# Generated by FakeRAM 2.0 (routing-friendly)
VERSION 5.7 ;
BUSBITCHARS "[]" ;
PROPERTYDEFINITIONS
  MACRO width INTEGER ;
  MACRO depth INTEGER ;
  MACRO banks INTEGER ;
END PROPERTYDEFINITIONS
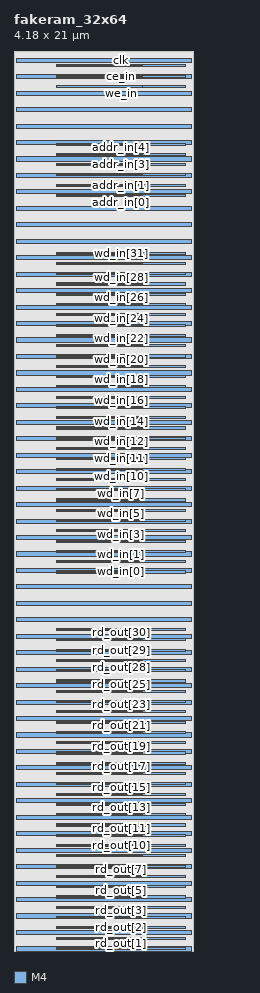
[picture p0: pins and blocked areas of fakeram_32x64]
MACRO fakeram_32x64
  PROPERTY width 32 ;
  PROPERTY depth 64 ;
  PROPERTY banks 1 ;
  FOREIGN fakeram_32x64 0 0 ;
  SYMMETRY X Y R90 ;
  SIZE 4.180 BY 21.000 ;
  CLASS BLOCK ;
  PIN rd_out[0]
    DIRECTION OUTPUT ;
    USE SIGNAL ;
    PORT
      LAYER M4 ;
      RECT 1.000 0.048 3.000 0.072 ;
    END
    PORT
      LAYER M4 ;
      RECT 1.000 0.036 4.000 0.084 ;
    END
  END rd_out[0]
  PIN rd_out[1]
    DIRECTION OUTPUT ;
    USE SIGNAL ;
    PORT
      LAYER M4 ;
      RECT 1.000 0.288 3.000 0.312 ;
    END
    PORT
      LAYER M4 ;
      RECT 1.000 0.276 4.000 0.324 ;
    END
  END rd_out[1]
  PIN rd_out[2]
    DIRECTION OUTPUT ;
    USE SIGNAL ;
    PORT
      LAYER M4 ;
      RECT 1.000 0.528 3.000 0.552 ;
    END
    PORT
      LAYER M4 ;
      RECT 1.000 0.516 4.000 0.564 ;
    END
  END rd_out[2]
  PIN rd_out[3]
    DIRECTION OUTPUT ;
    USE SIGNAL ;
    PORT
      LAYER M4 ;
      RECT 1.000 0.768 3.000 0.792 ;
    END
    PORT
      LAYER M4 ;
      RECT 1.000 0.756 4.000 0.804 ;
    END
  END rd_out[3]
  PIN rd_out[4]
    DIRECTION OUTPUT ;
    USE SIGNAL ;
    PORT
      LAYER M4 ;
      RECT 1.000 1.008 3.000 1.032 ;
    END
    PORT
      LAYER M4 ;
      RECT 1.000 0.996 4.000 1.044 ;
    END
  END rd_out[4]
  PIN rd_out[5]
    DIRECTION OUTPUT ;
    USE SIGNAL ;
    PORT
      LAYER M4 ;
      RECT 1.000 1.248 3.000 1.272 ;
    END
    PORT
      LAYER M4 ;
      RECT 1.000 1.236 4.000 1.284 ;
    END
  END rd_out[5]
  PIN rd_out[6]
    DIRECTION OUTPUT ;
    USE SIGNAL ;
    PORT
      LAYER M4 ;
      RECT 1.000 1.488 3.000 1.512 ;
    END
    PORT
      LAYER M4 ;
      RECT 1.000 1.476 4.000 1.524 ;
    END
  END rd_out[6]
  PIN rd_out[7]
    DIRECTION OUTPUT ;
    USE SIGNAL ;
    PORT
      LAYER M4 ;
      RECT 1.000 1.728 3.000 1.752 ;
    END
    PORT
      LAYER M4 ;
      RECT 1.000 1.716 4.000 1.764 ;
    END
  END rd_out[7]
  PIN rd_out[8]
    DIRECTION OUTPUT ;
    USE SIGNAL ;
    PORT
      LAYER M4 ;
      RECT 1.000 1.968 3.000 1.992 ;
    END
    PORT
      LAYER M4 ;
      RECT 1.000 1.956 4.000 2.004 ;
    END
  END rd_out[8]
  PIN rd_out[9]
    DIRECTION OUTPUT ;
    USE SIGNAL ;
    PORT
      LAYER M4 ;
      RECT 1.000 2.208 3.000 2.232 ;
    END
    PORT
      LAYER M4 ;
      RECT 1.000 2.196 4.000 2.244 ;
    END
  END rd_out[9]
  PIN rd_out[10]
    DIRECTION OUTPUT ;
    USE SIGNAL ;
    PORT
      LAYER M4 ;
      RECT 1.000 2.448 3.000 2.472 ;
    END
    PORT
      LAYER M4 ;
      RECT 1.000 2.436 4.000 2.484 ;
    END
  END rd_out[10]
  PIN rd_out[11]
    DIRECTION OUTPUT ;
    USE SIGNAL ;
    PORT
      LAYER M4 ;
      RECT 1.000 2.688 3.000 2.712 ;
    END
    PORT
      LAYER M4 ;
      RECT 1.000 2.676 4.000 2.724 ;
    END
  END rd_out[11]
  PIN rd_out[12]
    DIRECTION OUTPUT ;
    USE SIGNAL ;
    PORT
      LAYER M4 ;
      RECT 1.000 2.928 3.000 2.952 ;
    END
    PORT
      LAYER M4 ;
      RECT 1.000 2.916 4.000 2.964 ;
    END
  END rd_out[12]
  PIN rd_out[13]
    DIRECTION OUTPUT ;
    USE SIGNAL ;
    PORT
      LAYER M4 ;
      RECT 1.000 3.168 3.000 3.192 ;
    END
    PORT
      LAYER M4 ;
      RECT 1.000 3.156 4.000 3.204 ;
    END
  END rd_out[13]
  PIN rd_out[14]
    DIRECTION OUTPUT ;
    USE SIGNAL ;
    PORT
      LAYER M4 ;
      RECT 1.000 3.408 3.000 3.432 ;
    END
    PORT
      LAYER M4 ;
      RECT 1.000 3.396 4.000 3.444 ;
    END
  END rd_out[14]
  PIN rd_out[15]
    DIRECTION OUTPUT ;
    USE SIGNAL ;
    PORT
      LAYER M4 ;
      RECT 1.000 3.648 3.000 3.672 ;
    END
    PORT
      LAYER M4 ;
      RECT 1.000 3.636 4.000 3.684 ;
    END
  END rd_out[15]
  PIN rd_out[16]
    DIRECTION OUTPUT ;
    USE SIGNAL ;
    PORT
      LAYER M4 ;
      RECT 1.000 3.888 3.000 3.912 ;
    END
    PORT
      LAYER M4 ;
      RECT 1.000 3.876 4.000 3.924 ;
    END
  END rd_out[16]
  PIN rd_out[17]
    DIRECTION OUTPUT ;
    USE SIGNAL ;
    PORT
      LAYER M4 ;
      RECT 1.000 4.128 3.000 4.152 ;
    END
    PORT
      LAYER M4 ;
      RECT 1.000 4.116 4.000 4.164 ;
    END
  END rd_out[17]
  PIN rd_out[18]
    DIRECTION OUTPUT ;
    USE SIGNAL ;
    PORT
      LAYER M4 ;
      RECT 1.000 4.368 3.000 4.392 ;
    END
    PORT
      LAYER M4 ;
      RECT 1.000 4.356 4.000 4.404 ;
    END
  END rd_out[18]
  PIN rd_out[19]
    DIRECTION OUTPUT ;
    USE SIGNAL ;
    PORT
      LAYER M4 ;
      RECT 1.000 4.608 3.000 4.632 ;
    END
    PORT
      LAYER M4 ;
      RECT 1.000 4.596 4.000 4.644 ;
    END
  END rd_out[19]
  PIN rd_out[20]
    DIRECTION OUTPUT ;
    USE SIGNAL ;
    PORT
      LAYER M4 ;
      RECT 1.000 4.848 3.000 4.872 ;
    END
    PORT
      LAYER M4 ;
      RECT 1.000 4.836 4.000 4.884 ;
    END
  END rd_out[20]
  PIN rd_out[21]
    DIRECTION OUTPUT ;
    USE SIGNAL ;
    PORT
      LAYER M4 ;
      RECT 1.000 5.088 3.000 5.112 ;
    END
    PORT
      LAYER M4 ;
      RECT 1.000 5.076 4.000 5.124 ;
    END
  END rd_out[21]
  PIN rd_out[22]
    DIRECTION OUTPUT ;
    USE SIGNAL ;
    PORT
      LAYER M4 ;
      RECT 1.000 5.328 3.000 5.352 ;
    END
    PORT
      LAYER M4 ;
      RECT 1.000 5.316 4.000 5.364 ;
    END
  END rd_out[22]
  PIN rd_out[23]
    DIRECTION OUTPUT ;
    USE SIGNAL ;
    PORT
      LAYER M4 ;
      RECT 1.000 5.568 3.000 5.592 ;
    END
    PORT
      LAYER M4 ;
      RECT 1.000 5.556 4.000 5.604 ;
    END
  END rd_out[23]
  PIN rd_out[24]
    DIRECTION OUTPUT ;
    USE SIGNAL ;
    PORT
      LAYER M4 ;
      RECT 1.000 5.808 3.000 5.832 ;
    END
    PORT
      LAYER M4 ;
      RECT 1.000 5.796 4.000 5.844 ;
    END
  END rd_out[24]
  PIN rd_out[25]
    DIRECTION OUTPUT ;
    USE SIGNAL ;
    PORT
      LAYER M4 ;
      RECT 1.000 6.048 3.000 6.072 ;
    END
    PORT
      LAYER M4 ;
      RECT 1.000 6.036 4.000 6.084 ;
    END
  END rd_out[25]
  PIN rd_out[26]
    DIRECTION OUTPUT ;
    USE SIGNAL ;
    PORT
      LAYER M4 ;
      RECT 1.000 6.288 3.000 6.312 ;
    END
    PORT
      LAYER M4 ;
      RECT 1.000 6.276 4.000 6.324 ;
    END
  END rd_out[26]
  PIN rd_out[27]
    DIRECTION OUTPUT ;
    USE SIGNAL ;
    PORT
      LAYER M4 ;
      RECT 1.000 6.528 3.000 6.552 ;
    END
    PORT
      LAYER M4 ;
      RECT 1.000 6.516 4.000 6.564 ;
    END
  END rd_out[27]
  PIN rd_out[28]
    DIRECTION OUTPUT ;
    USE SIGNAL ;
    PORT
      LAYER M4 ;
      RECT 1.000 6.768 3.000 6.792 ;
    END
    PORT
      LAYER M4 ;
      RECT 1.000 6.756 4.000 6.804 ;
    END
  END rd_out[28]
  PIN rd_out[29]
    DIRECTION OUTPUT ;
    USE SIGNAL ;
    PORT
      LAYER M4 ;
      RECT 1.000 7.008 3.000 7.032 ;
    END
    PORT
      LAYER M4 ;
      RECT 1.000 6.996 4.000 7.044 ;
    END
  END rd_out[29]
  PIN rd_out[30]
    DIRECTION OUTPUT ;
    USE SIGNAL ;
    PORT
      LAYER M4 ;
      RECT 1.000 7.248 3.000 7.272 ;
    END
    PORT
      LAYER M4 ;
      RECT 1.000 7.236 4.000 7.284 ;
    END
  END rd_out[30]
  PIN rd_out[31]
    DIRECTION OUTPUT ;
    USE SIGNAL ;
    PORT
      LAYER M4 ;
      RECT 1.000 7.488 3.000 7.512 ;
    END
    PORT
      LAYER M4 ;
      RECT 1.000 7.476 4.000 7.524 ;
    END
  END rd_out[31]
  PIN wd_in[0]
    DIRECTION INPUT ;
    USE SIGNAL ;
    PORT
      LAYER M4 ;
      RECT 1.000 8.832 3.000 8.856 ;
    END
    PORT
      LAYER M4 ;
      RECT 1.000 8.820 4.000 8.868 ;
    END
  END wd_in[0]
  PIN wd_in[1]
    DIRECTION INPUT ;
    USE SIGNAL ;
    PORT
      LAYER M4 ;
      RECT 1.000 9.072 3.000 9.096 ;
    END
    PORT
      LAYER M4 ;
      RECT 1.000 9.060 4.000 9.108 ;
    END
  END wd_in[1]
  PIN wd_in[2]
    DIRECTION INPUT ;
    USE SIGNAL ;
    PORT
      LAYER M4 ;
      RECT 1.000 9.312 3.000 9.336 ;
    END
    PORT
      LAYER M4 ;
      RECT 1.000 9.300 4.000 9.348 ;
    END
  END wd_in[2]
  PIN wd_in[3]
    DIRECTION INPUT ;
    USE SIGNAL ;
    PORT
      LAYER M4 ;
      RECT 1.000 9.552 3.000 9.576 ;
    END
    PORT
      LAYER M4 ;
      RECT 1.000 9.540 4.000 9.588 ;
    END
  END wd_in[3]
  PIN wd_in[4]
    DIRECTION INPUT ;
    USE SIGNAL ;
    PORT
      LAYER M4 ;
      RECT 1.000 9.792 3.000 9.816 ;
    END
    PORT
      LAYER M4 ;
      RECT 1.000 9.780 4.000 9.828 ;
    END
  END wd_in[4]
  PIN wd_in[5]
    DIRECTION INPUT ;
    USE SIGNAL ;
    PORT
      LAYER M4 ;
      RECT 1.000 10.032 3.000 10.056 ;
    END
    PORT
      LAYER M4 ;
      RECT 1.000 10.020 4.000 10.068 ;
    END
  END wd_in[5]
  PIN wd_in[6]
    DIRECTION INPUT ;
    USE SIGNAL ;
    PORT
      LAYER M4 ;
      RECT 1.000 10.272 3.000 10.296 ;
    END
    PORT
      LAYER M4 ;
      RECT 1.000 10.260 4.000 10.308 ;
    END
  END wd_in[6]
  PIN wd_in[7]
    DIRECTION INPUT ;
    USE SIGNAL ;
    PORT
      LAYER M4 ;
      RECT 1.000 10.512 3.000 10.536 ;
    END
    PORT
      LAYER M4 ;
      RECT 1.000 10.500 4.000 10.548 ;
    END
  END wd_in[7]
  PIN wd_in[8]
    DIRECTION INPUT ;
    USE SIGNAL ;
    PORT
      LAYER M4 ;
      RECT 1.000 10.752 3.000 10.776 ;
    END
    PORT
      LAYER M4 ;
      RECT 1.000 10.740 4.000 10.788 ;
    END
  END wd_in[8]
  PIN wd_in[9]
    DIRECTION INPUT ;
    USE SIGNAL ;
    PORT
      LAYER M4 ;
      RECT 1.000 10.992 3.000 11.016 ;
    END
    PORT
      LAYER M4 ;
      RECT 1.000 10.980 4.000 11.028 ;
    END
  END wd_in[9]
  PIN wd_in[10]
    DIRECTION INPUT ;
    USE SIGNAL ;
    PORT
      LAYER M4 ;
      RECT 1.000 11.232 3.000 11.256 ;
    END
    PORT
      LAYER M4 ;
      RECT 1.000 11.220 4.000 11.268 ;
    END
  END wd_in[10]
  PIN wd_in[11]
    DIRECTION INPUT ;
    USE SIGNAL ;
    PORT
      LAYER M4 ;
      RECT 1.000 11.472 3.000 11.496 ;
    END
    PORT
      LAYER M4 ;
      RECT 1.000 11.460 4.000 11.508 ;
    END
  END wd_in[11]
  PIN wd_in[12]
    DIRECTION INPUT ;
    USE SIGNAL ;
    PORT
      LAYER M4 ;
      RECT 1.000 11.712 3.000 11.736 ;
    END
    PORT
      LAYER M4 ;
      RECT 1.000 11.700 4.000 11.748 ;
    END
  END wd_in[12]
  PIN wd_in[13]
    DIRECTION INPUT ;
    USE SIGNAL ;
    PORT
      LAYER M4 ;
      RECT 1.000 11.952 3.000 11.976 ;
    END
    PORT
      LAYER M4 ;
      RECT 1.000 11.940 4.000 11.988 ;
    END
  END wd_in[13]
  PIN wd_in[14]
    DIRECTION INPUT ;
    USE SIGNAL ;
    PORT
      LAYER M4 ;
      RECT 1.000 12.192 3.000 12.216 ;
    END
    PORT
      LAYER M4 ;
      RECT 1.000 12.180 4.000 12.228 ;
    END
  END wd_in[14]
  PIN wd_in[15]
    DIRECTION INPUT ;
    USE SIGNAL ;
    PORT
      LAYER M4 ;
      RECT 1.000 12.432 3.000 12.456 ;
    END
    PORT
      LAYER M4 ;
      RECT 1.000 12.420 4.000 12.468 ;
    END
  END wd_in[15]
  PIN wd_in[16]
    DIRECTION INPUT ;
    USE SIGNAL ;
    PORT
      LAYER M4 ;
      RECT 1.000 12.672 3.000 12.696 ;
    END
    PORT
      LAYER M4 ;
      RECT 1.000 12.660 4.000 12.708 ;
    END
  END wd_in[16]
  PIN wd_in[17]
    DIRECTION INPUT ;
    USE SIGNAL ;
    PORT
      LAYER M4 ;
      RECT 1.000 12.912 3.000 12.936 ;
    END
    PORT
      LAYER M4 ;
      RECT 1.000 12.900 4.000 12.948 ;
    END
  END wd_in[17]
  PIN wd_in[18]
    DIRECTION INPUT ;
    USE SIGNAL ;
    PORT
      LAYER M4 ;
      RECT 1.000 13.152 3.000 13.176 ;
    END
    PORT
      LAYER M4 ;
      RECT 1.000 13.140 4.000 13.188 ;
    END
  END wd_in[18]
  PIN wd_in[19]
    DIRECTION INPUT ;
    USE SIGNAL ;
    PORT
      LAYER M4 ;
      RECT 1.000 13.392 3.000 13.416 ;
    END
    PORT
      LAYER M4 ;
      RECT 1.000 13.380 4.000 13.428 ;
    END
  END wd_in[19]
  PIN wd_in[20]
    DIRECTION INPUT ;
    USE SIGNAL ;
    PORT
      LAYER M4 ;
      RECT 1.000 13.632 3.000 13.656 ;
    END
    PORT
      LAYER M4 ;
      RECT 1.000 13.620 4.000 13.668 ;
    END
  END wd_in[20]
  PIN wd_in[21]
    DIRECTION INPUT ;
    USE SIGNAL ;
    PORT
      LAYER M4 ;
      RECT 1.000 13.872 3.000 13.896 ;
    END
    PORT
      LAYER M4 ;
      RECT 1.000 13.860 4.000 13.908 ;
    END
  END wd_in[21]
  PIN wd_in[22]
    DIRECTION INPUT ;
    USE SIGNAL ;
    PORT
      LAYER M4 ;
      RECT 1.000 14.112 3.000 14.136 ;
    END
    PORT
      LAYER M4 ;
      RECT 1.000 14.100 4.000 14.148 ;
    END
  END wd_in[22]
  PIN wd_in[23]
    DIRECTION INPUT ;
    USE SIGNAL ;
    PORT
      LAYER M4 ;
      RECT 1.000 14.352 3.000 14.376 ;
    END
    PORT
      LAYER M4 ;
      RECT 1.000 14.340 4.000 14.388 ;
    END
  END wd_in[23]
  PIN wd_in[24]
    DIRECTION INPUT ;
    USE SIGNAL ;
    PORT
      LAYER M4 ;
      RECT 1.000 14.592 3.000 14.616 ;
    END
    PORT
      LAYER M4 ;
      RECT 1.000 14.580 4.000 14.628 ;
    END
  END wd_in[24]
  PIN wd_in[25]
    DIRECTION INPUT ;
    USE SIGNAL ;
    PORT
      LAYER M4 ;
      RECT 1.000 14.832 3.000 14.856 ;
    END
    PORT
      LAYER M4 ;
      RECT 1.000 14.820 4.000 14.868 ;
    END
  END wd_in[25]
  PIN wd_in[26]
    DIRECTION INPUT ;
    USE SIGNAL ;
    PORT
      LAYER M4 ;
      RECT 1.000 15.072 3.000 15.096 ;
    END
    PORT
      LAYER M4 ;
      RECT 1.000 15.060 4.000 15.108 ;
    END
  END wd_in[26]
  PIN wd_in[27]
    DIRECTION INPUT ;
    USE SIGNAL ;
    PORT
      LAYER M4 ;
      RECT 1.000 15.312 3.000 15.336 ;
    END
    PORT
      LAYER M4 ;
      RECT 1.000 15.300 4.000 15.348 ;
    END
  END wd_in[27]
  PIN wd_in[28]
    DIRECTION INPUT ;
    USE SIGNAL ;
    PORT
      LAYER M4 ;
      RECT 1.000 15.552 3.000 15.576 ;
    END
    PORT
      LAYER M4 ;
      RECT 1.000 15.540 4.000 15.588 ;
    END
  END wd_in[28]
  PIN wd_in[29]
    DIRECTION INPUT ;
    USE SIGNAL ;
    PORT
      LAYER M4 ;
      RECT 1.000 15.792 3.000 15.816 ;
    END
    PORT
      LAYER M4 ;
      RECT 1.000 15.780 4.000 15.828 ;
    END
  END wd_in[29]
  PIN wd_in[30]
    DIRECTION INPUT ;
    USE SIGNAL ;
    PORT
      LAYER M4 ;
      RECT 1.000 16.032 3.000 16.056 ;
    END
    PORT
      LAYER M4 ;
      RECT 1.000 16.020 4.000 16.068 ;
    END
  END wd_in[30]
  PIN wd_in[31]
    DIRECTION INPUT ;
    USE SIGNAL ;
    PORT
      LAYER M4 ;
      RECT 1.000 16.272 3.000 16.296 ;
    END
    PORT
      LAYER M4 ;
      RECT 1.000 16.260 4.000 16.308 ;
    END
  END wd_in[31]
  PIN addr_in[0]
    DIRECTION INPUT ;
    USE SIGNAL ;
    PORT
      LAYER M4 ;
      RECT 1.000 17.616 3.000 17.640 ;
    END
    PORT
      LAYER M4 ;
      RECT 1.000 17.604 4.000 17.652 ;
    END
  END addr_in[0]
  PIN addr_in[1]
    DIRECTION INPUT ;
    USE SIGNAL ;
    PORT
      LAYER M4 ;
      RECT 1.000 17.856 3.000 17.880 ;
    END
    PORT
      LAYER M4 ;
      RECT 1.000 17.844 4.000 17.892 ;
    END
  END addr_in[1]
  PIN addr_in[2]
    DIRECTION INPUT ;
    USE SIGNAL ;
    PORT
      LAYER M4 ;
      RECT 1.000 18.096 3.000 18.120 ;
    END
    PORT
      LAYER M4 ;
      RECT 1.000 18.084 4.000 18.132 ;
    END
  END addr_in[2]
  PIN addr_in[3]
    DIRECTION INPUT ;
    USE SIGNAL ;
    PORT
      LAYER M4 ;
      RECT 1.000 18.336 3.000 18.360 ;
    END
    PORT
      LAYER M4 ;
      RECT 1.000 18.324 4.000 18.372 ;
    END
  END addr_in[3]
  PIN addr_in[4]
    DIRECTION INPUT ;
    USE SIGNAL ;
    PORT
      LAYER M4 ;
      RECT 1.000 18.576 3.000 18.600 ;
    END
    PORT
      LAYER M4 ;
      RECT 1.000 18.564 4.000 18.612 ;
    END
  END addr_in[4]
  PIN addr_in[5]
    DIRECTION INPUT ;
    USE SIGNAL ;
    PORT
      LAYER M4 ;
      RECT 1.000 18.816 3.000 18.840 ;
    END
    PORT
      LAYER M4 ;
      RECT 1.000 18.804 4.000 18.852 ;
    END
  END addr_in[5]
  PIN we_in
    DIRECTION INPUT ;
    USE SIGNAL ;
    PORT
      LAYER M4 ;
      RECT 1.000 20.160 3.000 20.184 ;
    END
    PORT
      LAYER M4 ;
      RECT 1.000 20.148 4.000 20.196 ;
    END
  END we_in
  PIN ce_in
    DIRECTION INPUT ;
    USE SIGNAL ;
    PORT
      LAYER M4 ;
      RECT 1.000 20.400 3.000 20.424 ;
    END
    PORT
      LAYER M4 ;
      RECT 1.000 20.388 4.000 20.436 ;
    END
  END ce_in
  PIN clk
    DIRECTION INPUT ;
    USE SIGNAL ;
    PORT
      LAYER M4 ;
      RECT 1.000 20.640 3.000 20.664 ;
    END
    PORT
      LAYER M4 ;
      RECT 1.000 20.628 4.000 20.676 ;
    END
  END clk
  PIN VSS
    DIRECTION INOUT ;
    USE GROUND ;
    PORT
      LAYER M4 ;
      RECT 0.048 0.000 4.132 0.096 ;
      RECT 0.048 0.768 4.132 0.864 ;
      RECT 0.048 1.536 4.132 1.632 ;
      RECT 0.048 2.304 4.132 2.400 ;
      RECT 0.048 3.072 4.132 3.168 ;
      RECT 0.048 3.840 4.132 3.936 ;
      RECT 0.048 4.608 4.132 4.704 ;
      RECT 0.048 5.376 4.132 5.472 ;
      RECT 0.048 6.144 4.132 6.240 ;
      RECT 0.048 6.912 4.132 7.008 ;
      RECT 0.048 7.680 4.132 7.776 ;
      RECT 0.048 8.448 4.132 8.544 ;
      RECT 0.048 9.216 4.132 9.312 ;
      RECT 0.048 9.984 4.132 10.080 ;
      RECT 0.048 10.752 4.132 10.848 ;
      RECT 0.048 11.520 4.132 11.616 ;
      RECT 0.048 12.288 4.132 12.384 ;
      RECT 0.048 13.056 4.132 13.152 ;
      RECT 0.048 13.824 4.132 13.920 ;
      RECT 0.048 14.592 4.132 14.688 ;
      RECT 0.048 15.360 4.132 15.456 ;
      RECT 0.048 16.128 4.132 16.224 ;
      RECT 0.048 16.896 4.132 16.992 ;
      RECT 0.048 17.664 4.132 17.760 ;
      RECT 0.048 18.432 4.132 18.528 ;
      RECT 0.048 19.200 4.132 19.296 ;
      RECT 0.048 19.968 4.132 20.064 ;
      RECT 0.048 20.736 4.132 20.832 ;
    END
  END VSS
  PIN VDD
    DIRECTION INOUT ;
    USE POWER ;
    PORT
      LAYER M4 ;
      RECT 0.048 0.384 4.132 0.480 ;
      RECT 0.048 1.152 4.132 1.248 ;
      RECT 0.048 1.920 4.132 2.016 ;
      RECT 0.048 2.688 4.132 2.784 ;
      RECT 0.048 3.456 4.132 3.552 ;
      RECT 0.048 4.224 4.132 4.320 ;
      RECT 0.048 4.992 4.132 5.088 ;
      RECT 0.048 5.760 4.132 5.856 ;
      RECT 0.048 6.528 4.132 6.624 ;
      RECT 0.048 7.296 4.132 7.392 ;
      RECT 0.048 8.064 4.132 8.160 ;
      RECT 0.048 8.832 4.132 8.928 ;
      RECT 0.048 9.600 4.132 9.696 ;
      RECT 0.048 10.368 4.132 10.464 ;
      RECT 0.048 11.136 4.132 11.232 ;
      RECT 0.048 11.904 4.132 12.000 ;
      RECT 0.048 12.672 4.132 12.768 ;
      RECT 0.048 13.440 4.132 13.536 ;
      RECT 0.048 14.208 4.132 14.304 ;
      RECT 0.048 14.976 4.132 15.072 ;
      RECT 0.048 15.744 4.132 15.840 ;
      RECT 0.048 16.512 4.132 16.608 ;
      RECT 0.048 17.280 4.132 17.376 ;
      RECT 0.048 18.048 4.132 18.144 ;
      RECT 0.048 18.816 4.132 18.912 ;
      RECT 0.048 19.584 4.132 19.680 ;
      RECT 0.048 20.352 4.132 20.448 ;
    END
  END VDD
  OBS
    LAYER M1 ;
    RECT 0 0 4.180 21.000 ;
    LAYER M2 ;
    RECT 0 0 4.180 21.000 ;
    LAYER M3 ;
    RECT 0 0 4.180 21.000 ;
  END
END fakeram_32x64
END LIBRARY
